VERSION 5.7 ;
  NOWIREEXTENSIONATPIN ON ;
  DIVIDERCHAR "/" ;
  BUSBITCHARS "[]" ;
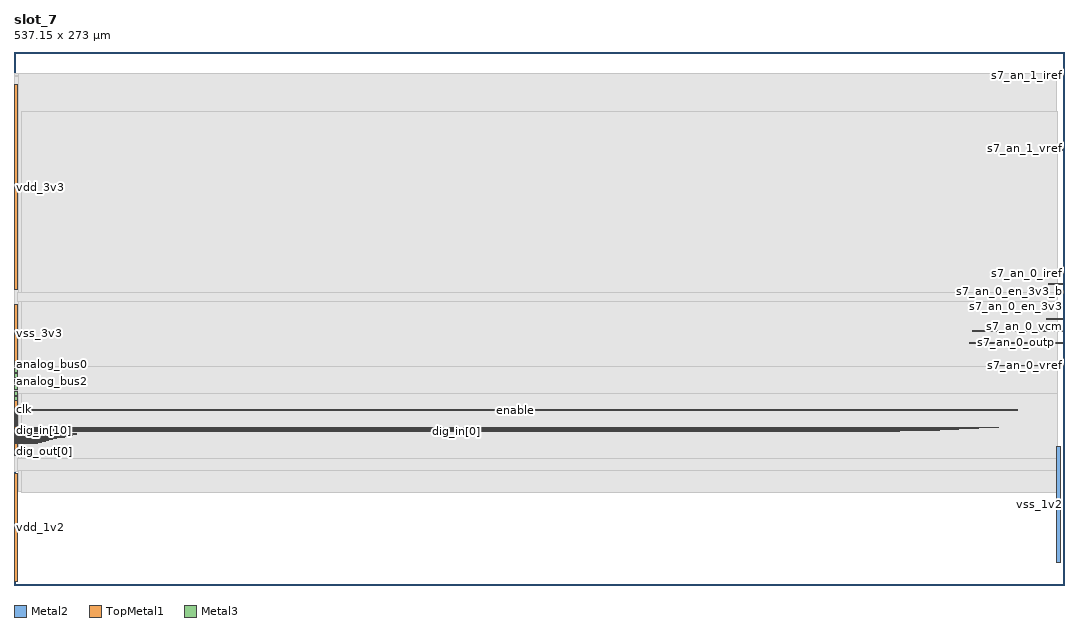
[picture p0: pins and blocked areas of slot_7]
MACRO slot_7
  CLASS BLOCK ;
  FOREIGN slot_7 ;
  ORIGIN 0.000 0.000 ;
  SIZE 537.150 BY 273.000 ;
  PIN vss_1v2
    PORT
      LAYER Metal2 ;
        RECT 533.150 11.635 535.150 71.055 ;
    END
    PORT
      LAYER TopMetal1 ;
        RECT 0.000 66.365 2.000 96.365 ;
    END
  END vss_1v2
  PIN vdd_1v2
    ANTENNAGATEAREA 2.700000 ;
    PORT
      LAYER TopMetal1 ;
        RECT 0.000 2.000 2.000 56.795 ;
    END
  END vdd_1v2
  PIN vss_3v3
    ANTENNAGATEAREA 190.511993 ;
    ANTENNADIFFAREA 625.374268 ;
    PORT
      LAYER TopMetal1 ;
        RECT 0.000 113.545 2.000 143.545 ;
    END
  END vss_3v3
  PIN vdd_3v3
    ANTENNAGATEAREA 43.599998 ;
    ANTENNADIFFAREA 393.669495 ;
    PORT
      LAYER TopMetal1 ;
        RECT 0.000 151.120 2.000 256.080 ;
    END
  END vdd_3v3
  PIN s7_an_0_vref
    ANTENNADIFFAREA 0.680000 ;
    PORT
      LAYER Metal3 ;
        RECT 502.580 112.115 536.450 112.405 ;
    END
  END s7_an_0_vref
  PIN s7_an_0_outp
    ANTENNADIFFAREA 2.040000 ;
    PORT
      LAYER Metal3 ;
        RECT 488.910 123.725 536.450 124.015 ;
    END
  END s7_an_0_outp
  PIN s7_an_0_outn
    ANTENNADIFFAREA 2.040000 ;
    PORT
      LAYER Metal3 ;
        RECT 490.270 129.825 536.450 130.115 ;
    END
  END s7_an_0_outn
  PIN s7_an_0_vcm
    ANTENNADIFFAREA 0.680000 ;
    PORT
      LAYER Metal3 ;
        RECT 528.300 135.875 536.450 136.165 ;
    END
  END s7_an_0_vcm
  PIN s7_an_0_en_3v3
    ANTENNAGATEAREA 13.049999 ;
    ANTENNADIFFAREA 0.680000 ;
    PORT
      LAYER Metal3 ;
        RECT 529.900 142.505 536.450 142.795 ;
    END
  END s7_an_0_en_3v3
  PIN s7_an_0_en_3v3_b
    ANTENNAGATEAREA 53.599998 ;
    ANTENNADIFFAREA 0.680000 ;
    PORT
      LAYER Metal3 ;
        RECT 529.100 153.695 536.450 153.985 ;
    END
  END s7_an_0_en_3v3_b
  PIN s7_an_0_iref
    ANTENNADIFFAREA 0.680000 ;
    PORT
      LAYER Metal3 ;
        RECT 531.500 159.365 536.450 159.655 ;
    END
  END s7_an_0_iref
  PIN s7_an_1_vinp
    ANTENNADIFFAREA 2.040000 ;
    PORT
      LAYER Metal3 ;
        RECT 527.500 222.115 536.450 222.405 ;
    END
  END s7_an_1_vinp
  PIN s7_an_1_vinn
    ANTENNADIFFAREA 2.040000 ;
    PORT
      LAYER Metal3 ;
        RECT 526.700 222.655 536.450 222.945 ;
    END
  END s7_an_1_vinn
  PIN s7_an_1_vref
    ANTENNADIFFAREA 0.680000 ;
    PORT
      LAYER Metal3 ;
        RECT 528.300 223.195 536.450 223.485 ;
    END
  END s7_an_1_vref
  PIN s7_an_1_iref
    ANTENNADIFFAREA 0.680000 ;
    PORT
      LAYER Metal3 ;
        RECT 530.700 260.455 536.450 260.745 ;
    END
  END s7_an_1_iref
  PIN s7_an_1_en_3v3_b
    ANTENNAGATEAREA 53.599998 ;
    ANTENNADIFFAREA 0.680000 ;
    PORT
      LAYER Metal3 ;
        RECT 529.100 260.995 536.450 261.285 ;
    END
  END s7_an_1_en_3v3_b
  PIN s7_an_1_en_3v3
    ANTENNAGATEAREA 13.049999 ;
    ANTENNADIFFAREA 0.680000 ;
    PORT
      LAYER Metal3 ;
        RECT 529.900 261.535 536.450 261.825 ;
    END
  END s7_an_1_en_3v3
  PIN vbias
    PORT
      LAYER Metal3 ;
        RECT 0.000 94.215 2.000 96.215 ;
    END
  END vbias
  PIN dig_in[23]
    PORT
      LAYER Metal3 ;
        RECT 0.000 88.470 2.000 88.690 ;
    END
  END dig_in[23]
  PIN dig_in[22]
    PORT
      LAYER Metal3 ;
        RECT 0.000 88.030 2.000 88.250 ;
    END
  END dig_in[22]
  PIN dig_in[21]
    PORT
      LAYER Metal3 ;
        RECT 0.000 87.590 2.000 87.810 ;
    END
  END dig_in[21]
  PIN dig_in[20]
    PORT
      LAYER Metal3 ;
        RECT 0.000 87.150 2.000 87.370 ;
    END
  END dig_in[20]
  PIN dig_in[19]
    PORT
      LAYER Metal3 ;
        RECT 0.000 86.710 2.000 86.930 ;
    END
  END dig_in[19]
  PIN dig_in[18]
    PORT
      LAYER Metal3 ;
        RECT 0.000 86.270 2.000 86.490 ;
    END
  END dig_in[18]
  PIN dig_in[17]
    PORT
      LAYER Metal3 ;
        RECT 0.000 85.830 2.000 86.050 ;
    END
  END dig_in[17]
  PIN dig_in[16]
    PORT
      LAYER Metal3 ;
        RECT 0.000 85.390 2.000 85.610 ;
    END
  END dig_in[16]
  PIN dig_in[15]
    PORT
      LAYER Metal3 ;
        RECT 0.000 84.950 2.000 85.170 ;
    END
  END dig_in[15]
  PIN dig_in[14]
    PORT
      LAYER Metal3 ;
        RECT 0.000 84.510 2.000 84.730 ;
    END
  END dig_in[14]
  PIN dig_in[13]
    PORT
      LAYER Metal3 ;
        RECT 0.000 84.070 2.000 84.290 ;
    END
  END dig_in[13]
  PIN dig_in[12]
    PORT
      LAYER Metal3 ;
        RECT 0.000 83.630 2.000 83.850 ;
    END
  END dig_in[12]
  PIN dig_in[11]
    PORT
      LAYER Metal3 ;
        RECT 0.000 83.190 2.000 83.410 ;
    END
  END dig_in[11]
  PIN dig_in[10]
    PORT
      LAYER Metal3 ;
        RECT 0.000 82.750 2.000 82.970 ;
    END
  END dig_in[10]
  PIN dig_in[9]
    PORT
      LAYER Metal3 ;
        RECT 0.000 82.310 2.000 82.530 ;
    END
  END dig_in[9]
  PIN dig_in[8]
    PORT
      LAYER Metal3 ;
        RECT 0.000 81.870 2.000 82.090 ;
    END
  END dig_in[8]
  PIN dig_in[7]
    PORT
      LAYER Metal3 ;
        RECT 0.000 81.430 2.000 81.650 ;
    END
  END dig_in[7]
  PIN dig_in[6]
    PORT
      LAYER Metal3 ;
        RECT 0.000 80.990 2.000 81.210 ;
    END
  END dig_in[6]
  PIN dig_in[5]
    ANTENNAGATEAREA 60.449997 ;
    PORT
      LAYER Metal3 ;
        RECT 0.000 80.550 503.495 80.770 ;
    END
  END dig_in[5]
  PIN dig_in[4]
    ANTENNAGATEAREA 60.449997 ;
    PORT
      LAYER Metal3 ;
        RECT 0.000 80.110 493.415 80.330 ;
    END
  END dig_in[4]
  PIN dig_in[3]
    ANTENNAGATEAREA 60.449997 ;
    PORT
      LAYER Metal3 ;
        RECT 0.000 79.670 483.335 79.890 ;
    END
  END dig_in[3]
  PIN dig_in[2]
    ANTENNAGATEAREA 60.449997 ;
    PORT
      LAYER Metal3 ;
        RECT 0.000 79.230 473.255 79.450 ;
    END
  END dig_in[2]
  PIN dig_in[1]
    ANTENNAGATEAREA 60.449997 ;
    PORT
      LAYER Metal3 ;
        RECT 0.000 78.790 463.175 79.010 ;
    END
  END dig_in[1]
  PIN dig_in[0]
    ANTENNAGATEAREA 60.449997 ;
    PORT
      LAYER Metal3 ;
        RECT 0.000 78.350 453.095 78.570 ;
    END
  END dig_in[0]
  PIN dig_out[11]
    ANTENNADIFFAREA 0.170000 ;
    PORT
      LAYER Metal3 ;
        RECT 0.000 77.030 31.880 77.250 ;
    END
  END dig_out[11]
  PIN dig_out[10]
    ANTENNADIFFAREA 0.170000 ;
    PORT
      LAYER Metal3 ;
        RECT 0.000 76.590 29.880 76.810 ;
    END
  END dig_out[10]
  PIN dig_out[9]
    ANTENNADIFFAREA 0.170000 ;
    PORT
      LAYER Metal3 ;
        RECT 0.000 76.150 27.880 76.370 ;
    END
  END dig_out[9]
  PIN dig_out[8]
    ANTENNADIFFAREA 0.170000 ;
    PORT
      LAYER Metal3 ;
        RECT 0.000 75.710 25.880 75.930 ;
    END
  END dig_out[8]
  PIN dig_out[7]
    ANTENNADIFFAREA 0.170000 ;
    PORT
      LAYER Metal3 ;
        RECT 0.000 75.270 23.880 75.490 ;
    END
  END dig_out[7]
  PIN dig_out[6]
    ANTENNADIFFAREA 0.170000 ;
    PORT
      LAYER Metal3 ;
        RECT 0.000 74.830 21.880 75.050 ;
    END
  END dig_out[6]
  PIN dig_out[5]
    ANTENNADIFFAREA 0.170000 ;
    PORT
      LAYER Metal3 ;
        RECT 0.000 74.390 19.880 74.610 ;
    END
  END dig_out[5]
  PIN dig_out[4]
    ANTENNADIFFAREA 0.170000 ;
    PORT
      LAYER Metal3 ;
        RECT 0.000 73.950 17.880 74.170 ;
    END
  END dig_out[4]
  PIN dig_out[3]
    ANTENNADIFFAREA 0.170000 ;
    PORT
      LAYER Metal3 ;
        RECT 0.000 73.510 15.880 73.730 ;
    END
  END dig_out[3]
  PIN dig_out[2]
    ANTENNADIFFAREA 0.170000 ;
    PORT
      LAYER Metal3 ;
        RECT 0.000 73.070 13.880 73.290 ;
    END
  END dig_out[2]
  PIN dig_out[1]
    ANTENNADIFFAREA 0.170000 ;
    PORT
      LAYER Metal3 ;
        RECT 0.000 72.630 11.880 72.850 ;
    END
  END dig_out[1]
  PIN dig_out[0]
    ANTENNADIFFAREA 0.170000 ;
    PORT
      LAYER Metal3 ;
        RECT 0.000 72.190 9.880 72.410 ;
    END
  END dig_out[0]
  PIN ibias0
    PORT
      LAYER Metal3 ;
        RECT 0.000 97.155 2.000 99.155 ;
    END
  END ibias0
  PIN ibias1
    PORT
      LAYER Metal3 ;
        RECT 0.000 100.095 2.000 102.095 ;
    END
  END ibias1
  PIN analog_bus3
    ANTENNADIFFAREA 0.680000 ;
    PORT
      LAYER Metal3 ;
        RECT 0.000 103.035 2.000 105.035 ;
    END
  END analog_bus3
  PIN analog_bus2
    ANTENNADIFFAREA 0.680000 ;
    PORT
      LAYER Metal3 ;
        RECT 0.000 105.975 2.000 107.975 ;
    END
  END analog_bus2
  PIN analog_bus1
    ANTENNADIFFAREA 1.360000 ;
    PORT
      LAYER Metal3 ;
        RECT 0.000 108.915 2.000 110.915 ;
    END
  END analog_bus1
  PIN analog_bus0
    ANTENNADIFFAREA 1.360000 ;
    PORT
      LAYER Metal3 ;
        RECT 0.000 111.855 2.000 113.855 ;
    END
  END analog_bus0
  PIN enable
    ANTENNAGATEAREA 60.449997 ;
    PORT
      LAYER Metal3 ;
        RECT 0.000 89.360 513.575 89.580 ;
    END
  END enable
  PIN clk
    PORT
      LAYER Metal3 ;
        RECT 0.000 89.800 2.000 90.020 ;
    END
  END clk
  PIN reset
    PORT
      LAYER Metal3 ;
        RECT 0.000 88.910 2.000 89.130 ;
    END
  END reset
  OBS
      LAYER GatPoly ;
        RECT 8.500 60.000 522.945 225.840 ;
      LAYER Metal1 ;
        RECT 2.500 59.850 533.200 225.820 ;
      LAYER Metal2 ;
        RECT 2.500 71.265 533.200 228.155 ;
        RECT 2.500 58.300 532.940 71.265 ;
      LAYER Metal3 ;
        RECT 0.000 261.495 529.690 261.825 ;
        RECT 0.000 260.785 528.890 261.495 ;
        RECT 0.000 260.245 530.490 260.785 ;
        RECT 0.000 223.695 533.200 260.245 ;
        RECT 0.000 223.155 528.090 223.695 ;
        RECT 0.000 222.445 526.490 223.155 ;
        RECT 0.000 221.905 527.290 222.445 ;
        RECT 0.000 159.865 533.200 221.905 ;
        RECT 0.000 159.155 531.290 159.865 ;
        RECT 0.000 154.195 533.200 159.155 ;
        RECT 0.000 153.485 528.890 154.195 ;
        RECT 0.000 143.005 533.200 153.485 ;
        RECT 0.000 142.295 529.690 143.005 ;
        RECT 0.000 136.375 533.200 142.295 ;
        RECT 0.000 135.665 528.090 136.375 ;
        RECT 0.000 130.325 533.200 135.665 ;
        RECT 0.000 129.615 490.060 130.325 ;
        RECT 0.000 124.225 533.200 129.615 ;
        RECT 0.000 123.515 488.700 124.225 ;
        RECT 0.000 114.065 533.200 123.515 ;
        RECT 2.210 112.615 533.200 114.065 ;
        RECT 2.210 111.905 502.370 112.615 ;
        RECT 2.210 111.645 533.200 111.905 ;
        RECT 0.000 111.125 533.200 111.645 ;
        RECT 2.210 108.705 533.200 111.125 ;
        RECT 0.000 108.185 533.200 108.705 ;
        RECT 2.210 105.765 533.200 108.185 ;
        RECT 0.000 105.245 533.200 105.765 ;
        RECT 2.210 102.825 533.200 105.245 ;
        RECT 0.000 102.305 533.200 102.825 ;
        RECT 2.210 99.885 533.200 102.305 ;
        RECT 0.000 99.365 533.200 99.885 ;
        RECT 2.210 96.945 533.200 99.365 ;
        RECT 0.000 96.425 533.200 96.945 ;
        RECT 2.210 94.005 533.200 96.425 ;
        RECT 0.000 90.230 533.200 94.005 ;
        RECT 2.210 89.790 533.200 90.230 ;
        RECT 513.785 89.150 533.200 89.790 ;
        RECT 2.210 80.980 533.200 89.150 ;
        RECT 503.705 80.340 533.200 80.980 ;
        RECT 493.625 79.900 533.200 80.340 ;
        RECT 483.545 79.460 533.200 79.900 ;
        RECT 473.465 79.020 533.200 79.460 ;
        RECT 463.385 78.580 533.200 79.020 ;
        RECT 453.305 78.140 533.200 78.580 ;
        RECT 0.000 77.460 533.200 78.140 ;
        RECT 32.090 76.820 533.200 77.460 ;
        RECT 30.090 76.380 533.200 76.820 ;
        RECT 28.090 75.940 533.200 76.380 ;
        RECT 26.090 75.500 533.200 75.940 ;
        RECT 24.090 75.060 533.200 75.500 ;
        RECT 22.090 74.620 533.200 75.060 ;
        RECT 20.090 74.180 533.200 74.620 ;
        RECT 18.090 73.740 533.200 74.180 ;
        RECT 16.090 73.300 533.200 73.740 ;
        RECT 14.090 72.860 533.200 73.300 ;
        RECT 12.090 72.420 533.200 72.860 ;
        RECT 10.090 71.980 533.200 72.420 ;
        RECT 0.000 58.300 533.200 71.980 ;
      LAYER Metal4 ;
        RECT 2.500 48.000 533.200 261.830 ;
      LAYER TopMetal1 ;
        RECT 3.640 149.480 534.000 242.000 ;
        RECT 2.000 145.185 534.000 149.480 ;
        RECT 3.640 111.905 534.000 145.185 ;
        RECT 2.000 98.005 534.000 111.905 ;
        RECT 3.640 64.725 534.000 98.005 ;
        RECT 2.000 58.435 534.000 64.725 ;
        RECT 3.640 47.200 534.000 58.435 ;
  END
END slot_7
END LIBRARY

